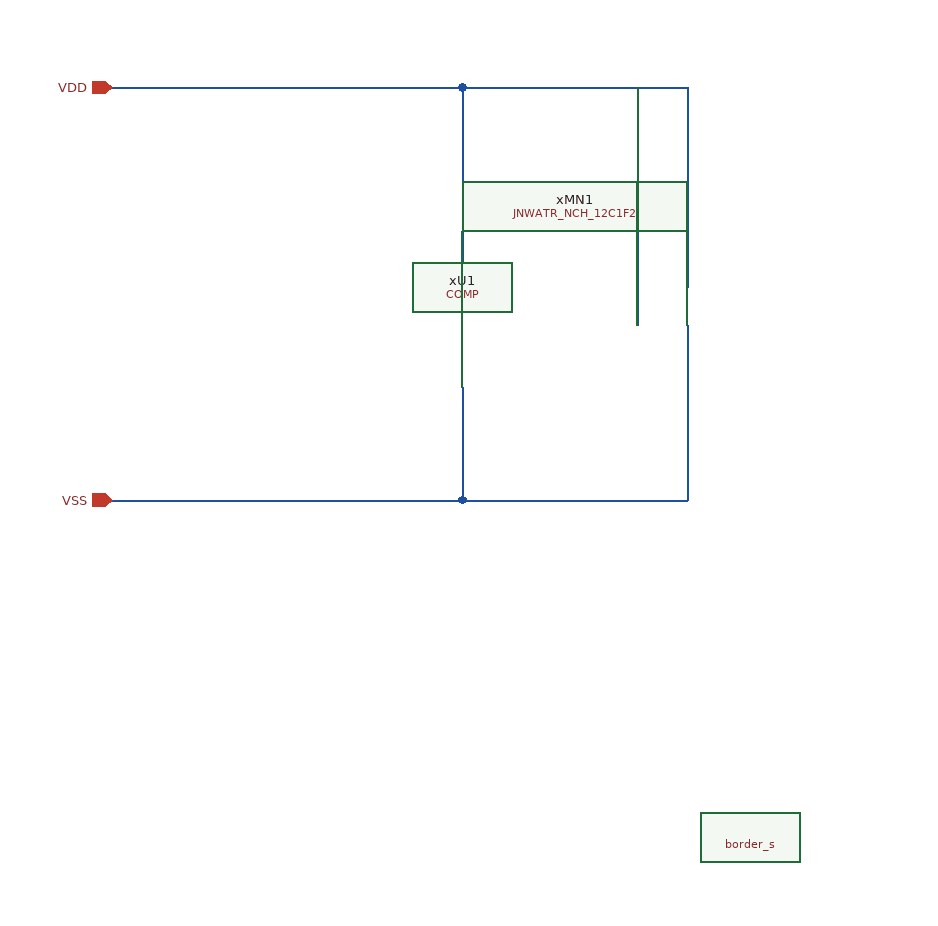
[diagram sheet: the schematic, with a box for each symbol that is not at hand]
v {xschem version=3.4.6 file_version=1.2}
G {}
K {}
V {}
S {}
E {}
N 900 -810 1050 -810 {lab=VDD}
N 900 -480 1050 -480 {lab=VSS}
N 1180 -810 1180 -670 {lab=VDD}
N 1050 -810 1180 -810 {lab=VDD}
N 1180 -570 1180 -480 {lab=VSS}
N 1050 -480 1180 -480 {lab=VSS}
N 1180 -810 1310 -810 {lab=VDD}
N 1180 -480 1310 -480 {lab=VSS}
N 1310 -810 1360 -810 {lab=VDD}
N 1360 -810 1360 -670 {lab=VDD}
N 1360 -570 1360 -480 {lab=VSS}
N 1310 -480 1360 -480 {lab=VSS}
N 1360 -670 1360 -650 {lab=VDD}
N 1360 -620 1360 -590 {lab=VSS}
N 1360 -590 1360 -570 {lab=VSS}
N 1320 -810 1320 -620 {lab=VDD}
C {cborder/border_s.sym} 1410 -210 0 0 {
user="bkle"
company="bkle"}
C {devices/ipin.sym} 900 -810 0 0 {name=p1 lab=VDD}
C {devices/ipin.sym} 900 -480 0 0 {name=p2 lab=VSS}
C {JNW_BKLE_SKY130A/COMP.sym} 1060 -720 0 0 {name=xU1}
C {JNW_ATR_SKY130A/JNWATR_NCH_12C1F2.sym} 1320 -620 0 0 {name=xMN1}
